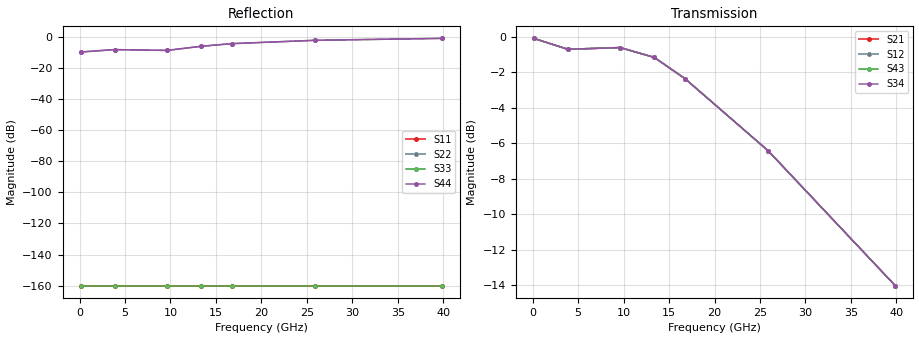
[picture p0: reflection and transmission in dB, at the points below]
! 26-Jun-2017 15:42:12
# Hz S RI R 50
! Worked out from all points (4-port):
!   319 points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, 125 MHz to 39.88 GHz, reference 50 ohm
!   strongest paths, dB at 125 MHz, 10 GHz, 20 GHz, 30 GHz, 39.88 GHz:
!     S43: -0.1, -0.6, -3.6, -8.8, -14.0
!     S21: -0.1, -0.6, -3.6, -8.8, -14.0
!     S42: -, -, -, -, -
!     S41: -, -, -, -, -
!     S32: -, -, -, -, -
!     S31: -, -, -, -, -
!   lowest |S11| = - dB at 125 MHz (marker M1), VSWR 1.00, Z = 50 + j0 ohm
!   |S11| at or under -10 dB: start of sweep to end of sweep
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1.25e8  0 0  0.991 -0.0221  0 0  0 0
        0.991 -0.0221  -0.3197 -0.00324  0 0  0 0
        0 0  0 0  0 0  0.991 -0.0221
        0 0  0 0  0.991 -0.0221  -0.3197 -0.00324
3.875e9  0 0  0.7512 -0.537  0 0  0 0
         0.7512 -0.537  -0.3812 -0.023  0 0  0 0
         0 0  0 0  0 0  0.7512 -0.537
         0 0  0 0  0.7512 -0.537  -0.3812 -0.023
9.625e9  0 0  0.0911 -0.9294  0 0  0 0
         0.0911 -0.9294  -0.3589 -0.0212  0 0  0 0
         0 0  0 0  0 0  0.0911 -0.9294
         0 0  0 0  0.0911 -0.9294  -0.3589 -0.0212
1.3375e10  0 0  -0.4737 -0.7369  0 0  0 0
           -0.4737 -0.7369  -0.4816 -0.0808  0 0  0 0
           0 0  0 0  0 0  -0.4737 -0.7369
           0 0  0 0  -0.4737 -0.7369  -0.4816 -0.0808
1.675e10  0 0  -0.69 -0.3267  0 0  0 0
          -0.69 -0.3267  -0.5939 -0.00674  0 0  0 0
          0 0  0 0  0 0  -0.69 -0.3267
          0 0  0 0  -0.69 -0.3267  -0.5939 -0.00674
2.5875e10  0 0  -0.284 0.3852  0 0  0 0
           -0.284 0.3852  -0.7145 0.257  0 0  0 0
           0 0  0 0  0 0  -0.284 0.3852
           0 0  0 0  -0.284 0.3852  -0.7145 0.257
3.9875e10  0 0  0.1892 0.0621  0 0  0 0
           0.1892 0.0621  -0.8206 0.3086  0 0  0 0
           0 0  0 0  0 0  0.1892 0.0621
           0 0  0 0  0.1892 0.0621  -0.8206 0.3086
